One B-rep face of a CAD part: STEP entity #54054.
In plain terms, the planar face has unit normal (0, 0, 1).
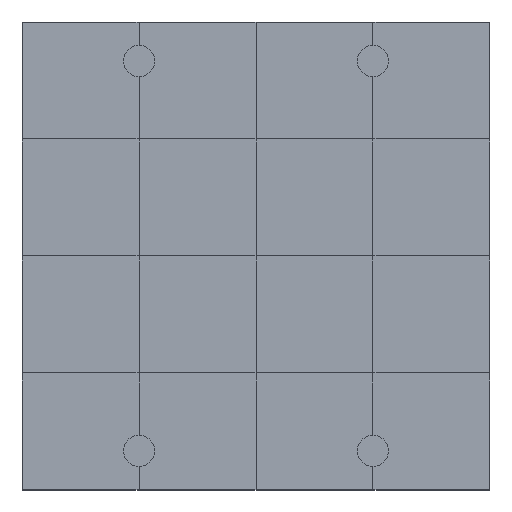
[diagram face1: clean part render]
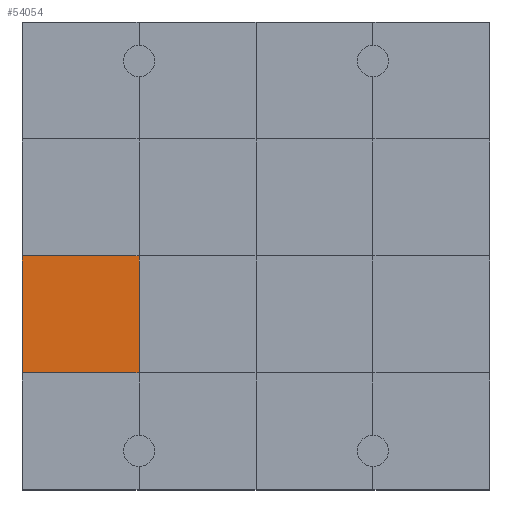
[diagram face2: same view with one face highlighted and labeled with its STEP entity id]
Its self-contained STEP definition (entity closure, numbers rounded to 3 decimals):
#53604 = VERTEX_POINT('',#53605);
#53605 = CARTESIAN_POINT('',(0.,3.,1.2));
#53619 = PLANE('',#53620);
#53620 = AXIS2_PLACEMENT_3D('',#53621,#53622,#53623);
#53621 = CARTESIAN_POINT('',(0.,3.,0.));
#53622 = DIRECTION('',(1.,0.,-0.));
#53623 = DIRECTION('',(0.,0.,1.));
#53645 = PLANE('',#53646);
#53646 = AXIS2_PLACEMENT_3D('',#53647,#53648,#53649);
#53647 = CARTESIAN_POINT('',(0.,0.,1.2));
#53648 = DIRECTION('',(0.,0.,1.));
#53649 = DIRECTION('',(1.,0.,-0.));
#53796 = VERTEX_POINT('',#53797);
#53797 = CARTESIAN_POINT('',(3.,3.,1.2));
#53818 = EDGE_CURVE('',#53604,#53796,#53819,.T.);
#53819 = SURFACE_CURVE('',#53820,(#53824,#53831),.PCURVE_S1.);
#53820 = LINE('',#53821,#53822);
#53821 = CARTESIAN_POINT('',(0.,3.,1.2));
#53822 = VECTOR('',#53823,1.);
#53823 = DIRECTION('',(1.,0.,-0.));
#53824 = PCURVE('',#53645,#53825);
#53825 = DEFINITIONAL_REPRESENTATION('',(#53826),#53830);
#53826 = LINE('',#53827,#53828);
#53827 = CARTESIAN_POINT('',(0.,3.));
#53828 = VECTOR('',#53829,1.);
#53829 = DIRECTION('',(1.,0.));
#53830 = ( GEOMETRIC_REPRESENTATION_CONTEXT(2) 
PARAMETRIC_REPRESENTATION_CONTEXT() REPRESENTATION_CONTEXT('2D SPACE',''
  ) );
#53831 = PCURVE('',#53832,#53837);
#53832 = PLANE('',#53833);
#53833 = AXIS2_PLACEMENT_3D('',#53834,#53835,#53836);
#53834 = CARTESIAN_POINT('',(0.,3.,1.2));
#53835 = DIRECTION('',(0.,0.,1.));
#53836 = DIRECTION('',(1.,0.,-0.));
#53837 = DEFINITIONAL_REPRESENTATION('',(#53838),#53842);
#53838 = LINE('',#53839,#53840);
#53839 = CARTESIAN_POINT('',(0.,0.));
#53840 = VECTOR('',#53841,1.);
#53841 = DIRECTION('',(1.,0.));
#53842 = ( GEOMETRIC_REPRESENTATION_CONTEXT(2) 
PARAMETRIC_REPRESENTATION_CONTEXT() REPRESENTATION_CONTEXT('2D SPACE',''
  ) );
#53877 = VERTEX_POINT('',#53878);
#53878 = CARTESIAN_POINT('',(0.,6.,1.2));
#53904 = EDGE_CURVE('',#53604,#53877,#53905,.T.);
#53905 = SURFACE_CURVE('',#53906,(#53910,#53917),.PCURVE_S1.);
#53906 = LINE('',#53907,#53908);
#53907 = CARTESIAN_POINT('',(0.,3.,1.2));
#53908 = VECTOR('',#53909,1.);
#53909 = DIRECTION('',(-0.,1.,0.));
#53910 = PCURVE('',#53619,#53911);
#53911 = DEFINITIONAL_REPRESENTATION('',(#53912),#53916);
#53912 = LINE('',#53913,#53914);
#53913 = CARTESIAN_POINT('',(1.2,0.));
#53914 = VECTOR('',#53915,1.);
#53915 = DIRECTION('',(0.,-1.));
#53916 = ( GEOMETRIC_REPRESENTATION_CONTEXT(2) 
PARAMETRIC_REPRESENTATION_CONTEXT() REPRESENTATION_CONTEXT('2D SPACE',''
  ) );
#53917 = PCURVE('',#53832,#53918);
#53918 = DEFINITIONAL_REPRESENTATION('',(#53919),#53923);
#53919 = LINE('',#53920,#53921);
#53920 = CARTESIAN_POINT('',(0.,0.));
#53921 = VECTOR('',#53922,1.);
#53922 = DIRECTION('',(0.,1.));
#53923 = ( GEOMETRIC_REPRESENTATION_CONTEXT(2) 
PARAMETRIC_REPRESENTATION_CONTEXT() REPRESENTATION_CONTEXT('2D SPACE',''
  ) );
#54054 = ADVANCED_FACE('',(#54055),#53832,.T.);
#54055 = FACE_BOUND('',#54056,.T.);
#54056 = EDGE_LOOP('',(#54057,#54058,#54059,#54087));
#54057 = ORIENTED_EDGE('',*,*,#53904,.F.);
#54058 = ORIENTED_EDGE('',*,*,#53818,.T.);
#54059 = ORIENTED_EDGE('',*,*,#54060,.T.);
#54060 = EDGE_CURVE('',#53796,#54061,#54063,.T.);
#54061 = VERTEX_POINT('',#54062);
#54062 = CARTESIAN_POINT('',(3.,6.,1.2));
#54063 = SURFACE_CURVE('',#54064,(#54068,#54075),.PCURVE_S1.);
#54064 = LINE('',#54065,#54066);
#54065 = CARTESIAN_POINT('',(3.,3.,1.2));
#54066 = VECTOR('',#54067,1.);
#54067 = DIRECTION('',(-0.,1.,0.));
#54068 = PCURVE('',#53832,#54069);
#54069 = DEFINITIONAL_REPRESENTATION('',(#54070),#54074);
#54070 = LINE('',#54071,#54072);
#54071 = CARTESIAN_POINT('',(3.,0.));
#54072 = VECTOR('',#54073,1.);
#54073 = DIRECTION('',(0.,1.));
#54074 = ( GEOMETRIC_REPRESENTATION_CONTEXT(2) 
PARAMETRIC_REPRESENTATION_CONTEXT() REPRESENTATION_CONTEXT('2D SPACE',''
  ) );
#54075 = PCURVE('',#54076,#54081);
#54076 = PLANE('',#54077);
#54077 = AXIS2_PLACEMENT_3D('',#54078,#54079,#54080);
#54078 = CARTESIAN_POINT('',(3.,3.,1.2));
#54079 = DIRECTION('',(0.,0.,1.));
#54080 = DIRECTION('',(1.,0.,-0.));
#54081 = DEFINITIONAL_REPRESENTATION('',(#54082),#54086);
#54082 = LINE('',#54083,#54084);
#54083 = CARTESIAN_POINT('',(0.,0.));
#54084 = VECTOR('',#54085,1.);
#54085 = DIRECTION('',(0.,1.));
#54086 = ( GEOMETRIC_REPRESENTATION_CONTEXT(2) 
PARAMETRIC_REPRESENTATION_CONTEXT() REPRESENTATION_CONTEXT('2D SPACE',''
  ) );
#54087 = ORIENTED_EDGE('',*,*,#54088,.F.);
#54088 = EDGE_CURVE('',#53877,#54061,#54089,.T.);
#54089 = SURFACE_CURVE('',#54090,(#54094,#54101),.PCURVE_S1.);
#54090 = LINE('',#54091,#54092);
#54091 = CARTESIAN_POINT('',(0.,6.,1.2));
#54092 = VECTOR('',#54093,1.);
#54093 = DIRECTION('',(1.,0.,-0.));
#54094 = PCURVE('',#53832,#54095);
#54095 = DEFINITIONAL_REPRESENTATION('',(#54096),#54100);
#54096 = LINE('',#54097,#54098);
#54097 = CARTESIAN_POINT('',(0.,3.));
#54098 = VECTOR('',#54099,1.);
#54099 = DIRECTION('',(1.,0.));
#54100 = ( GEOMETRIC_REPRESENTATION_CONTEXT(2) 
PARAMETRIC_REPRESENTATION_CONTEXT() REPRESENTATION_CONTEXT('2D SPACE',''
  ) );
#54101 = PCURVE('',#54102,#54107);
#54102 = PLANE('',#54103);
#54103 = AXIS2_PLACEMENT_3D('',#54104,#54105,#54106);
#54104 = CARTESIAN_POINT('',(0.,6.,1.2));
#54105 = DIRECTION('',(0.,0.,1.));
#54106 = DIRECTION('',(1.,0.,-0.));
#54107 = DEFINITIONAL_REPRESENTATION('',(#54108),#54112);
#54108 = LINE('',#54109,#54110);
#54109 = CARTESIAN_POINT('',(0.,0.));
#54110 = VECTOR('',#54111,1.);
#54111 = DIRECTION('',(1.,0.));
#54112 = ( GEOMETRIC_REPRESENTATION_CONTEXT(2) 
PARAMETRIC_REPRESENTATION_CONTEXT() REPRESENTATION_CONTEXT('2D SPACE',''
  ) );
